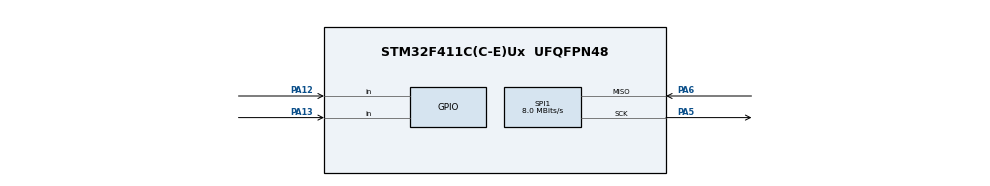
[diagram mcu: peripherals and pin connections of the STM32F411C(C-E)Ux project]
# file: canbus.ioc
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Mcu.Family=STM32F4
Mcu.Name=STM32F411C(C-E)Ux
Mcu.Package=UFQFPN48
NVIC.PriorityGroup=NVIC_PRIORITYGROUP_4
PA11.Signal=SPI4_MISO
PA12.Signal=GPIO_Input
PA13.Signal=GPIO_Input
PA5.Mode=RX_Only_Simplex_Unidirect_Master
PA5.Signal=SPI1_SCK
PA6.Mode=RX_Only_Simplex_Unidirect_Master
PA6.Signal=SPI1_MISO
ProjectManager.HeapSize=0x200
ProjectManager.StackSize=0x400
ProjectManager.TargetToolchain=STM32CubeIDE
RCC.AHBFreq_Value=16000000
RCC.APB1Freq_Value=16000000
RCC.APB2Freq_Value=16000000
RCC.CortexFreq_Value=16000000
RCC.HSE_VALUE=25000000
RCC.HSI_VALUE=16000000
RCC.LSE_VALUE=32768
RCC.SYSCLKFreq_VALUE=16000000
RCC.VCOOutputFreq_Value=192000000
SPI1.CalculateBaudRate=8.0 MBits/s
SPI1.Direction=SPI_DIRECTION_2LINES_RXONLY
SPI1.Mode=SPI_MODE_MASTER
SPI1.VirtualType=VM_MASTER
board=custom

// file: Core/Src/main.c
/* USER CODE BEGIN Header */
/**
  ******************************************************************************
  * @file           : main.c
  * @brief          : Main program body
  ******************************************************************************
  * @attention
  *
  * Copyright (c) 2024 STMicroelectronics.
  * All rights reserved.
  *
  * This software is licensed under terms that can be found in the LICENSE file
  * in the root directory of this software component.
  * If no LICENSE file comes with this software, it is provided AS-IS.
  *
  ******************************************************************************
  */
/* USER CODE END Header */
#include "main.h"
#include "mcp2515.h"
#include "can.h"

SPI_HandleTypeDef hspi1;
struct can_frame can_msg;

void SystemClock_Config(void);
static void MX_GPIO_Init(void);
static void MX_SPI1_Init(void);

int main(void)
{

  /* MCU Configuration--------------------------------------------------------*/

  /* Reset of all peripherals, Initializes the Flash interface and the Systick. */
  HAL_Init();

  /* Configure the system clock */
  SystemClock_Config();

  /* Initialize all configured peripherals */
  MX_GPIO_Init();
  MX_SPI1_Init();
  /* USER CODE BEGIN 2 */
  //MCP2515 mcp;
  //MCP2515_init(mcp, _CS, _SPI_CLOCK);
  if(MCP2515_reset(&hspi1) != ERROR_OK)
  {
	  //shutdown bike
  }
  if (set_bitrate_125kbps(&hspi1) != ERROR_OK)
  {
	  //shutdown bike
  }
  if (setMode(CANCTRL_REQOP_NORMAL, &hspi1) != ERROR_OK)
  {
	  //shutdown bike
  }

  /* USER CODE END 2 */

  /* Infinite loop */
  while (1)
  {

    /* USER CODE BEGIN 3 */

	  if (readMessage(&can_msg, &hspi1) == ERROR_OK)
	  {
		 //we are reading the message here
	  }
  }
  /* USER CODE END 3 */
}

void SystemClock_Config(void)
{
  RCC_OscInitTypeDef RCC_OscInitStruct = {0};
  RCC_ClkInitTypeDef RCC_ClkInitStruct = {0};

  /** Configure the main internal regulator output voltage
  */
  __HAL_RCC_PWR_CLK_ENABLE();
  __HAL_PWR_VOLTAGESCALING_CONFIG(PWR_REGULATOR_VOLTAGE_SCALE1);

  /** Initializes the RCC Oscillators according to the specified parameters
  * in the RCC_OscInitTypeDef structure.
  */
  RCC_OscInitStruct.OscillatorType = RCC_OSCILLATORTYPE_HSI;
  RCC_OscInitStruct.HSIState = RCC_HSI_ON;
  RCC_OscInitStruct.HSICalibrationValue = RCC_HSICALIBRATION_DEFAULT;
  RCC_OscInitStruct.PLL.PLLState = RCC_PLL_ON;
  RCC_OscInitStruct.PLL.PLLSource = RCC_PLLSOURCE_HSI;
  RCC_OscInitStruct.PLL.PLLM = 8;
  RCC_OscInitStruct.PLL.PLLN = 80;
  RCC_OscInitStruct.PLL.PLLP = RCC_PLLP_DIV2;
  RCC_OscInitStruct.PLL.PLLQ = 4;
  if (HAL_RCC_OscConfig(&RCC_OscInitStruct) != HAL_OK)
  {
    Error_Handler();
  }

  /** Initializes the CPU, AHB and APB buses clocks
  */
  RCC_ClkInitStruct.ClockType = RCC_CLOCKTYPE_HCLK|RCC_CLOCKTYPE_SYSCLK
                              |RCC_CLOCKTYPE_PCLK1|RCC_CLOCKTYPE_PCLK2;
  RCC_ClkInitStruct.SYSCLKSource = RCC_SYSCLKSOURCE_PLLCLK;
  RCC_ClkInitStruct.AHBCLKDivider = RCC_SYSCLK_DIV8;
  RCC_ClkInitStruct.APB1CLKDivider = RCC_HCLK_DIV1;
  RCC_ClkInitStruct.APB2CLKDivider = RCC_HCLK_DIV1;

  if (HAL_RCC_ClockConfig(&RCC_ClkInitStruct, FLASH_LATENCY_0) != HAL_OK)
  {
    Error_Handler();
  }
}

static void MX_SPI1_Init(void)
{

  /* SPI1 parameter configuration*/
  hspi1.Instance = SPI1;
  hspi1.Init.Mode = SPI_MODE_MASTER;
  hspi1.Init.Direction = SPI_DIRECTION_2LINES;
  hspi1.Init.DataSize = SPI_DATASIZE_8BIT;
  hspi1.Init.CLKPolarity = SPI_POLARITY_LOW;
  hspi1.Init.CLKPhase = SPI_PHASE_1EDGE;
  hspi1.Init.NSS = SPI_NSS_SOFT;
  hspi1.Init.BaudRatePrescaler = SPI_BAUDRATEPRESCALER_2;
  hspi1.Init.FirstBit = SPI_FIRSTBIT_MSB;
  hspi1.Init.TIMode = SPI_TIMODE_DISABLE;
  hspi1.Init.CRCCalculation = SPI_CRCCALCULATION_DISABLE;
  hspi1.Init.CRCPolynomial = 10;
  if (HAL_SPI_Init(&hspi1) != HAL_OK)
  {
    Error_Handler();
  }

}

static void MX_GPIO_Init(void)
{
  GPIO_InitTypeDef GPIO_InitStruct = {0};

  /* GPIO Ports Clock Enable */
  __HAL_RCC_GPIOA_CLK_ENABLE();
  __HAL_RCC_GPIOB_CLK_ENABLE();

  /*Configure GPIO pin Output Level */
  HAL_GPIO_WritePin(SPI1_CS_GPIO_Port, SPI1_CS_Pin, GPIO_PIN_SET);

  /*Configure GPIO pin : SPI1_CS_Pin */
  GPIO_InitStruct.Pin = SPI1_CS_Pin;
  GPIO_InitStruct.Mode = GPIO_MODE_OUTPUT_PP;
  GPIO_InitStruct.Pull = GPIO_NOPULL;
  GPIO_InitStruct.Speed = GPIO_SPEED_FREQ_LOW;
  HAL_GPIO_Init(SPI1_CS_GPIO_Port, &GPIO_InitStruct);

}

void Error_Handler(void)
{
  __disable_irq();
  while (1)
  {
  }
}
